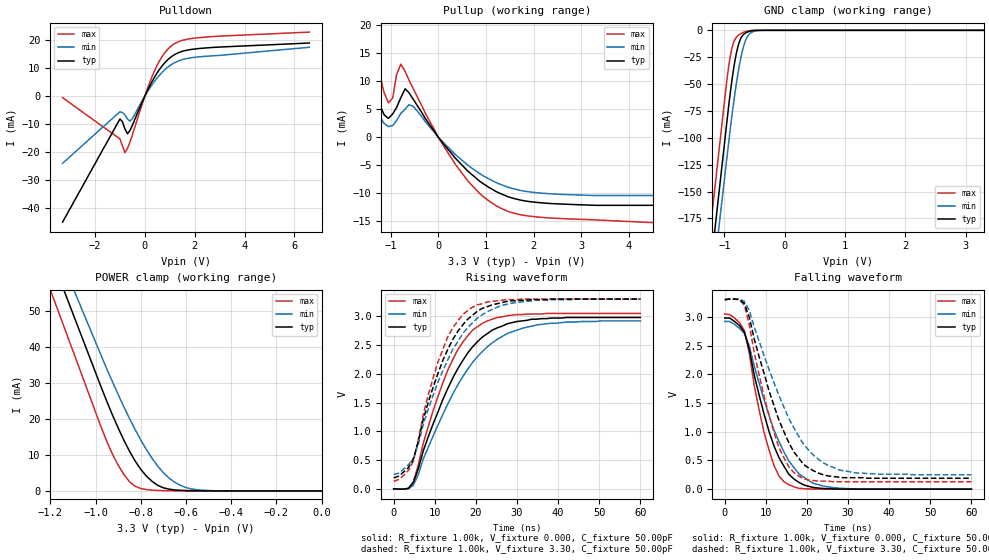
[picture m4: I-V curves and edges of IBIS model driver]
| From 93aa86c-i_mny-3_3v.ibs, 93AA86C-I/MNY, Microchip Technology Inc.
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|   Model driver
[Model]   driver
Model_type   3-state
Vmeas = 1.65
C_comp   5.00pF   5.00pF   5.00pF
[Temperature Range]   25.00   85.00   -40.00
[Voltage Range]   3.30V   1.80V   5.50V
[Pullup Reference]   3.30V   3.30V   3.30V
[POWER Clamp Reference]   3.30V   3.30V   3.30V
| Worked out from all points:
|   slope of the pulldown table from 0 to 0.495 V, typ, clamps not added: 59.7 ohm
|   slope of the pullup table from 0 to 0.495 V, typ, clamps not added: 100 ohm
|   GND clamp passes 1 mA (typ) near -0.59 V on its own axis
|   POWER clamp passes 1 mA (typ) near -0.70 V on its own axis
|   rising waveform, R_fixture 1.00k, V_fixture 0.000, C_fixture 50.00pF: 20-80 % time 11.3ns typ, 13.3ns min, 9.17ns max; typ from 0 V to 2.98 V
|   rising waveform, R_fixture 1.00k, V_fixture 3.30, C_fixture 50.00pF: 20-80 % time 9.14ns typ, 10.4ns min, 7.61ns max; typ from 0.19 V to 3.3 V
|   falling waveform, R_fixture 1.00k, V_fixture 0.000, C_fixture 50.00pF: 20-80 % time 6.8ns typ, 8.37ns min, 5.35ns max; typ from 2.98 V to 0 V
|   falling waveform, R_fixture 1.00k, V_fixture 3.30, C_fixture 50.00pF: 20-80 % time 8.6ns typ, 10.7ns min, 6.53ns max; typ from 3.3 V to 0.19 V
[GND_clamp]
| voltage   I(typ)   I(min)   I(max)
-3.3V     -1.265A    -1.261A    -1.229A
-1.26V    -236.7mA   -265.5mA   -197.9mA
-1.175V   -193.9mA   -224mA     -155mA
-1.09V    -151.1mA   -182.5mA   -112mA
-950mV    -80.54mA   -114.2mA   -42.22mA
-900mV    -56.85mA   -90.32mA   -23.12mA
-850mV    -36.55mA   -68.47mA   -11.58mA
-800mV    -20.78mA   -48.82mA   -6.385mA
-700mV    -4.893mA   -18.64mA   -2.236mA
-600mV    -1.233mA   -4.325mA   -417.6uA
-425mV    -18.71uA   -165.9uA   -518.5nA
3.3V      10pA       10pA       10pA
[POWER_clamp]
| voltage   I(typ)   I(min)   I(max)
-3.3V     408.2mA    387.2mA    412mA
-1.2V     65.48mA    71.36mA    55.8mA
-1.175V   61.4mA     67.6mA     51.56mA
-1.125V   53.24mA    60.08mA    43.08mA
-1.1V     49.16mA    56.32mA    38.84mA
-1.075V   45.08mA    52.56mA    34.6mA
-900mV    17.47mA    26.75mA    7.159mA
-825mV    8.309mA    17.03mA    1.312mA
-750mV    2.652mA    9.023mA    222.9uA
-675mV    494.1uA    3.561mA    44.53uA
-575mV    58.81uA    551.3uA    1.642uA
0V        10pA       10pA       10pA
[Pulldown]
| voltage   I(typ)   I(min)   I(max)
-3.3V     -44.94mA   -23.97mA   -543.3uA
-1V       -8.144mA   -5.569mA   -15.26mA
-800mV    -11.71mA   -6.719mA   -20.15mA
-700mV    -13.42mA   -8.109mA   -18.67mA
-600mV    -12.29mA   -8.934mA   -16.47mA
-500mV    -10.39mA   -8.036mA   -13.83mA
0V        0A         0A         0A
400mV     6.923mA    5.389mA    9.245mA
700mV     10.85mA    8.537mA    14.21mA
1.1V      14.27mA    11.43mA    18.15mA
2.2V      16.98mA    14.02mA    20.85mA
6.6V      18.93mA    17.4mA     22.82mA
[Pullup]
| voltage   I(typ)   I(min)   I(max)
-3.3V     46.2mA     31.77mA    81.28mA
-2.44V    29.27mA    20.02mA    51.9mA
-2V       20.8mA     14.15mA    37.21mA
-1.49V    10.63mA    7.088mA    19.57mA
-1.05V    3.352mA    1.882mA    6.145mA
-960mV    4.172mA    2.087mA    7.003mA
-790mV    7.078mA    4.271mA    13.06mA
-700mV    8.653mA    5.013mA    11.77mA
-530mV    6.791mA    5.519mA    8.672mA
430mV     -4.431mA   -3.66mA    -5.729mA
1.47V     -10.68mA   -8.973mA   -13.3mA
6.6V      -12.19mA   -10.44mA   -16.12mA
[Ramp]
| variable   typ   min   max
dV/dt_r   1.79/0.73n   1.75/0.95n   1.83/0.61n
dV/dt_f   1.86/0.94n   1.83/1.04n   1.90/0.60n
R_load = 1.00k
[Rising Waveform]
R_fixture = 1.00k
V_fixture = 0.000
C_fixture = 50.00pF
| time   V(typ)   V(min)   V(max)
0s        -49.93uV   -28.91uV   -99.5uV
3.6ns     9.57mV     810uV      5.25mV
4.8ns     110mV      61.3mV     120mV
8.4ns     900mV      720mV      1.08V
12ns      1.56V      1.3V       1.85V
15.6ns    2.09V      1.81V      2.42V
19.2ns    2.47V      2.2V       2.76V
24ns      2.76V      2.54V      2.95V
31.2ns    2.92V      2.79V      3.03V
60ns      2.98V      2.92V      3.05V
[Rising Waveform]
R_fixture = 1.00k
V_fixture = 3.30
C_fixture = 50.00pF
| time   V(typ)   V(min)   V(max)
0s        190mV      250mV      130mV
2.4ns     290mV      340mV      230mV
4.8ns     520mV      530mV      480mV
7.2ns     1.21V      1.12V      1.29V
10.8ns    2.01V      1.86V      2.21V
14.4ns    2.6V       2.43V      2.8V
18ns      2.95V      2.8V       3.1V
22.8ns    3.17V      3.08V      3.25V
28.8ns    3.27V      3.23V      3.29V
60ns      3.3V       3.3V       3.3V
[Falling Waveform]
R_fixture = 1.00k
V_fixture = 0.000
C_fixture = 50.00pF
| time   V(typ)   V(min)   V(max)
0s        2.98V      2.92V      3.05V
2.4ns     2.92V      2.87V      2.98V
4.8ns     2.73V      2.71V      2.76V
6ns       2.43V      2.49V      2.36V
9.6ns     1.3V       1.55V      980mV
12ns      750mV      1.03V      410mV
14.4ns    400mV      650mV      130mV
18ns      120mV      270mV      16.03mV
24ns      11.68mV    53.47mV    290uV
60ns      48.51nV    1.54uV     46.19nV
[Falling Waveform]
R_fixture = 1.00k
V_fixture = 3.30
C_fixture = 50.00pF
| time   V(typ)   V(min)   V(max)
0s        3.3V       3.3V       3.3V
4.8ns     3.23V      3.27V      3.2V
6ns       2.99V      3.11V      2.86V
7.2ns     2.61V      2.82V      2.37V
10.8ns    1.71V      2.08V      1.28V
13.2ns    1.2V       1.63V      720mV
16.8ns    650mV      1.07V      290mV
21.6ns    320mV      590mV      150mV
27.6ns    210mV      340mV      130mV
60ns      190mV      250mV      130mV
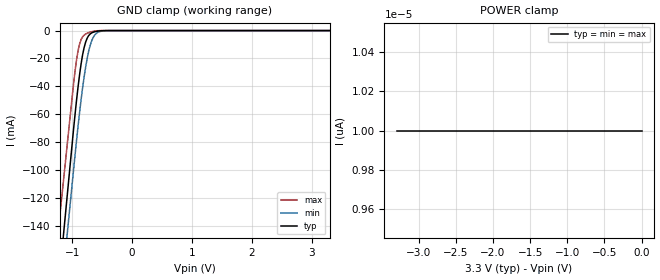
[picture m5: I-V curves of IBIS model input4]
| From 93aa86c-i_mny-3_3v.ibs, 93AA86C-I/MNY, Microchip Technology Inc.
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|   Model input4
[Model]   input4
Model_type   Input
Vinl = 0.8
Vinh = 2.0
C_comp   5.00pF   5.00pF   5.00pF
[Temperature Range]   25.00   85.00   -40.00
[Voltage Range]   3.30V   1.80V   5.50V
[Pullup Reference]   3.30V   3.30V   3.30V
[POWER Clamp Reference]   3.30V   3.30V   3.30V
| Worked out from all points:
|   GND clamp passes 1 mA (typ) near -0.64 V on its own axis
[GND_clamp]
| voltage   I(typ)   I(min)   I(max)
-3.3V     -1.115A    -1.108A    -995.6mA
-1.26V    -198.2mA   -223mA     -155.1mA
-1.175V   -160.1mA   -186.2mA   -120.1mA
-1.09V    -121.9mA   -149.3mA   -85.06mA
-975mV    -70.22mA   -99.35mA   -37.68mA
-925mV    -49.41mA   -78.18mA   -20.61mA
-875mV    -31.46mA   -58.47mA   -9.556mA
-825mV    -17.36mA   -40.96mA   -4.459mA
-750mV    -5.561mA   -20.24mA   -1.962mA
-650mV    -1.203mA   -5.041mA   -547.3uA
-475mV    -44.27uA   -228.5uA   -4.811uA
3.3V      -67.28nA   -53.27nA   -87.39nA
[POWER_clamp]
| voltage   I(typ)   I(min)   I(max)
-3.3V     10pA       10pA       10pA
-3.23V    10pA       10pA       10pA
-3.16V    10pA       10pA       10pA
0V        10pA       10pA       10pA
